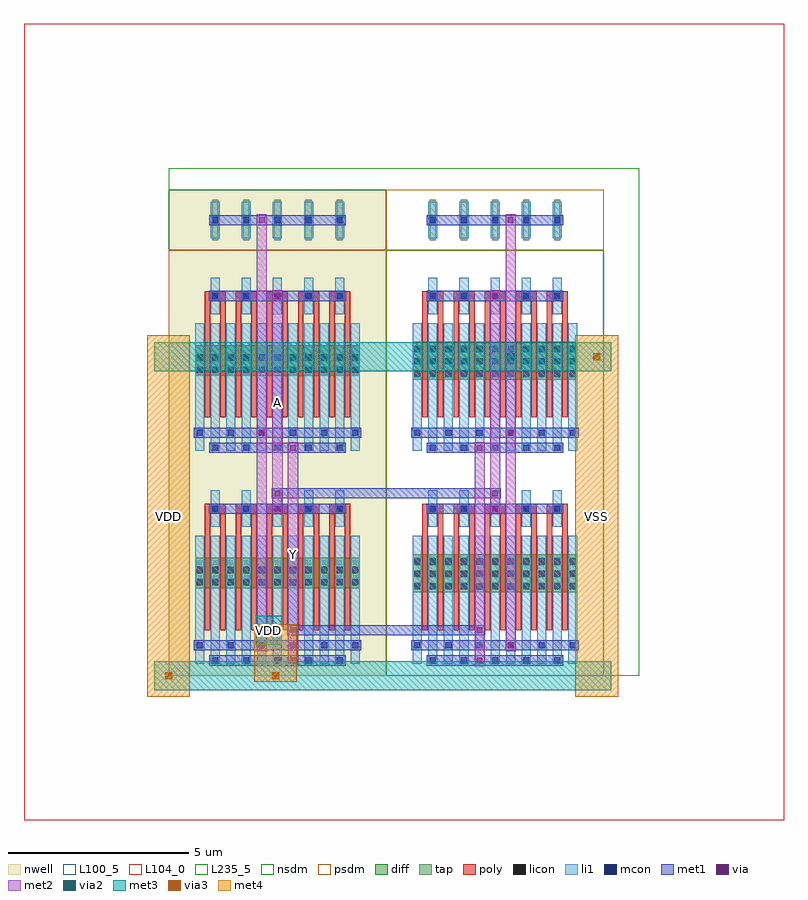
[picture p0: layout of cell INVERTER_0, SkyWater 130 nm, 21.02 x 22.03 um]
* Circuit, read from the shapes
.subckt INVERTER_0 A VDD VSS Y
XM1 Y A VSS VSS sky130_fd_pr__nfet_01v8 w=1.05 l=0.15 m=20
XM2 Y A VDD VDD sky130_fd_pr__pfet_01v8 w=0.84 l=0.15 m=20
.ends

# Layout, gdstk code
from math import pi, radians
import gdstk
lib = gdstk.Library(unit=1e-6, precision=1e-09)
def R(c, l, rs):  # rectangles x0, y0, x1, y1
    for r in rs: c.add(gdstk.rectangle(r[:2], r[2:], *l))
def A(c, l, x, y, w, h, nx, ny, dx, dy):  # array of equal rectangles
    R(c, l, [(x+i*dx, y+j*dy, x+i*dx+w, y+j*dy+h) for i in range(nx) for j in range(ny)])
def P(c, l, *ps):  # polygons
    for p in ps: c.add(gdstk.Polygon(p, *l))
nwell = (64, 20)
diff = (65, 20)
tap = (65, 44)
poly = (66, 20)
licon = (66, 44)
li1 = (67, 20)
mcon = (67, 44)
met1 = (68, 20)
via = (68, 44)
met2 = (69, 20)
via2 = (69, 44)
met3 = (70, 20)
via3 = (70, 44)
met4 = (71, 20)
nsdm = (93, 44)
psdm = (94, 20)
L100_5 = (100, 5)
L104_0 = (104, 0)
L235_5 = (235, 5)

nmos_s_6078655_x5_y2_167 = lib.new_cell('NMOS_S_6078655_X5_Y2_1678793193')
R(nmos_s_6078655_x5_y2_167, diff, [(0.735,2.31,5.285,3.36), (0.735,8.19,5.285,9.24)])
A(nmos_s_6078655_x5_y2_167, tap, 1.205, 12.04, 0.17, 1.12, 5, 1, 0.86, 0)
A(nmos_s_6078655_x5_y2_167, poly, 1, 1.26, 0.15, 3.36, 10, 2, 0.43, 5.88)
A(nmos_s_6078655_x5_y2_167, poly, 1, 4.485, 0.58, 0.27, 5, 2, 0.86, 5.88)
A(nmos_s_6078655_x5_y2_167, licon, 0.775, 2.39, 0.17, 0.17, 3, 3, 0.43, 0.34)
A(nmos_s_6078655_x5_y2_167, licon, 1.635, 2.39, 0.17, 0.17, 3, 3, 0.43, 0.34)
A(nmos_s_6078655_x5_y2_167, licon, 2.495, 2.39, 0.17, 0.17, 3, 3, 0.43, 0.34)
A(nmos_s_6078655_x5_y2_167, licon, 3.355, 2.39, 0.17, 0.17, 3, 3, 0.43, 0.34)
A(nmos_s_6078655_x5_y2_167, licon, 4.215, 2.39, 0.17, 0.17, 3, 3, 0.43, 0.34)
A(nmos_s_6078655_x5_y2_167, licon, 1.205, 4.535, 0.17, 0.17, 5, 2, 0.86, 5.88)
A(nmos_s_6078655_x5_y2_167, licon, 0.775, 8.27, 0.17, 0.17, 3, 3, 0.43, 0.34)
A(nmos_s_6078655_x5_y2_167, licon, 1.635, 8.27, 0.17, 0.17, 3, 3, 0.43, 0.34)
A(nmos_s_6078655_x5_y2_167, licon, 2.495, 8.27, 0.17, 0.17, 3, 3, 0.43, 0.34)
A(nmos_s_6078655_x5_y2_167, licon, 3.355, 8.27, 0.17, 0.17, 3, 3, 0.43, 0.34)
A(nmos_s_6078655_x5_y2_167, licon, 4.215, 8.27, 0.17, 0.17, 3, 3, 0.43, 0.34)
R(nmos_s_6078655_x5_y2_167, licon, [(1.205,12.515,1.375,12.685), (1.205,12.515,1.375,12.685), (2.065,12.515,2.235,12.685), (2.065,12.515,2.235,12.685), (2.925,12.515,3.095,12.685), (2.925,12.515,3.095,12.685), (3.785,12.515,3.955,12.685), (3.785,12.515,3.955,12.685), (4.645,12.515,4.815,12.685), (4.645,12.515,4.815,12.685)])
A(nmos_s_6078655_x5_y2_167, li1, 0.735, 0.335, 0.25, 3.53, 11, 2, 0.43, 5.88)
A(nmos_s_6078655_x5_y2_167, li1, 1.165, 4.115, 0.25, 1.01, 5, 2, 0.86, 5.88)
A(nmos_s_6078655_x5_y2_167, li1, 1.165, 12.095, 0.25, 1.01, 5, 1, 0.86, 0)
A(nmos_s_6078655_x5_y2_167, mcon, 1.205, 0.335, 0.17, 0.17, 5, 2, 0.86, 4.2)
A(nmos_s_6078655_x5_y2_167, mcon, 0.775, 0.755, 0.17, 0.17, 6, 2, 0.86, 5.88)
A(nmos_s_6078655_x5_y2_167, mcon, 1.205, 6.215, 0.17, 0.17, 5, 2, 0.86, 4.2)
A(nmos_s_6078655_x5_y2_167, mcon, 1.205, 12.515, 0.17, 0.17, 5, 1, 0.86, 0)
R(nmos_s_6078655_x5_y2_167, met1, [(1.12,0.28,4.9,0.56), (0.69,0.7,5.33,0.98), (1.12,4.48,4.9,4.76), (1.12,6.16,4.9,6.44), (0.69,6.58,5.33,6.86), (1.12,10.36,4.9,10.64), (1.12,12.46,4.9,12.74)])
A(nmos_s_6078655_x5_y2_167, via, 3.365, 0.765, 0.15, 0.15, 1, 3, 0, 5.88)
R(nmos_s_6078655_x5_y2_167, via, [(2.505,0.345,2.655,0.495), (2.935,4.545,3.085,4.695), (2.505,6.225,2.655,6.375), (2.935,10.425,3.085,10.575)])
R(nmos_s_6078655_x5_y2_167, met2, [(2.44,0.26,2.72,6.46), (3.3,0.68,3.58,12.76), (2.87,4.46,3.15,10.66)])
R(nmos_s_6078655_x5_y2_167, nsdm, [(0,0,6.02,11.76)])
R(nmos_s_6078655_x5_y2_167, psdm, [(0,11.76,6.02,13.44)])
R(nmos_s_6078655_x5_y2_167, L100_5, [(0,0,6.02,13.44)])

pmos_s_79543009_x5_y2_16 = lib.new_cell('PMOS_S_79543009_X5_Y2_1678793194')
R(pmos_s_79543009_x5_y2_16, nwell, [(0,0,6.02,13.44)])
R(pmos_s_79543009_x5_y2_16, diff, [(0.735,2.415,5.285,3.255), (0.735,8.295,5.285,9.135)])
A(pmos_s_79543009_x5_y2_16, tap, 1.205, 12.04, 0.17, 1.12, 5, 1, 0.86, 0)
A(pmos_s_79543009_x5_y2_16, poly, 1, 1.26, 0.15, 3.36, 10, 2, 0.43, 5.88)
A(pmos_s_79543009_x5_y2_16, poly, 1, 4.485, 0.58, 0.27, 5, 2, 0.86, 5.88)
A(pmos_s_79543009_x5_y2_16, licon, 0.775, 2.495, 0.17, 0.17, 3, 2, 0.43, 0.34)
A(pmos_s_79543009_x5_y2_16, licon, 1.635, 2.495, 0.17, 0.17, 3, 2, 0.43, 0.34)
A(pmos_s_79543009_x5_y2_16, licon, 2.495, 2.495, 0.17, 0.17, 3, 2, 0.43, 0.34)
A(pmos_s_79543009_x5_y2_16, licon, 3.355, 2.495, 0.17, 0.17, 3, 2, 0.43, 0.34)
A(pmos_s_79543009_x5_y2_16, licon, 4.215, 2.495, 0.17, 0.17, 3, 2, 0.43, 0.34)
A(pmos_s_79543009_x5_y2_16, licon, 1.205, 4.535, 0.17, 0.17, 5, 2, 0.86, 5.88)
A(pmos_s_79543009_x5_y2_16, licon, 0.775, 8.375, 0.17, 0.17, 3, 2, 0.43, 0.34)
A(pmos_s_79543009_x5_y2_16, licon, 1.635, 8.375, 0.17, 0.17, 3, 2, 0.43, 0.34)
A(pmos_s_79543009_x5_y2_16, licon, 2.495, 8.375, 0.17, 0.17, 3, 2, 0.43, 0.34)
A(pmos_s_79543009_x5_y2_16, licon, 3.355, 8.375, 0.17, 0.17, 3, 2, 0.43, 0.34)
A(pmos_s_79543009_x5_y2_16, licon, 4.215, 8.375, 0.17, 0.17, 3, 2, 0.43, 0.34)
R(pmos_s_79543009_x5_y2_16, licon, [(1.205,12.515,1.375,12.685), (1.205,12.515,1.375,12.685), (2.065,12.515,2.235,12.685), (2.065,12.515,2.235,12.685), (2.925,12.515,3.095,12.685), (2.925,12.515,3.095,12.685), (3.785,12.515,3.955,12.685), (3.785,12.515,3.955,12.685), (4.645,12.515,4.815,12.685), (4.645,12.515,4.815,12.685)])
A(pmos_s_79543009_x5_y2_16, li1, 0.735, 0.335, 0.25, 3.53, 11, 2, 0.43, 5.88)
A(pmos_s_79543009_x5_y2_16, li1, 1.165, 4.115, 0.25, 1.01, 5, 2, 0.86, 5.88)
A(pmos_s_79543009_x5_y2_16, li1, 1.165, 12.095, 0.25, 1.01, 5, 1, 0.86, 0)
A(pmos_s_79543009_x5_y2_16, mcon, 1.205, 0.335, 0.17, 0.17, 5, 2, 0.86, 4.2)
A(pmos_s_79543009_x5_y2_16, mcon, 0.775, 0.755, 0.17, 0.17, 6, 2, 0.86, 5.88)
A(pmos_s_79543009_x5_y2_16, mcon, 1.205, 6.215, 0.17, 0.17, 5, 2, 0.86, 4.2)
A(pmos_s_79543009_x5_y2_16, mcon, 1.205, 12.515, 0.17, 0.17, 5, 1, 0.86, 0)
R(pmos_s_79543009_x5_y2_16, met1, [(1.12,0.28,4.9,0.56), (0.69,0.7,5.33,0.98), (1.12,4.48,4.9,4.76), (1.12,6.16,4.9,6.44), (0.69,6.58,5.33,6.86), (1.12,10.36,4.9,10.64), (1.12,12.46,4.9,12.74)])
A(pmos_s_79543009_x5_y2_16, via, 3.365, 0.765, 0.15, 0.15, 1, 3, 0, 5.88)
R(pmos_s_79543009_x5_y2_16, via, [(2.505,0.345,2.655,0.495), (2.935,4.545,3.085,4.695), (2.505,6.225,2.655,6.375), (2.935,10.425,3.085,10.575)])
R(pmos_s_79543009_x5_y2_16, met2, [(2.44,0.26,2.72,6.46), (3.3,0.68,3.58,12.76), (2.87,4.46,3.15,10.66)])
R(pmos_s_79543009_x5_y2_16, nsdm, [(0,11.76,6.02,13.44)])
R(pmos_s_79543009_x5_y2_16, psdm, [(0,0,6.02,11.76)])
R(pmos_s_79543009_x5_y2_16, L100_5, [(0,0,6.02,13.44)])

inverter_0 = lib.new_cell('INVERTER_0')
R(inverter_0, met1, [(3.28,1.12,3.6,1.4), (3.28,1.12,3.6,1.4), (3.44,1.12,8.6,1.4), (8.44,1.12,8.76,1.4), (8.44,1.12,8.76,1.4), (2.85,4.9,3.17,5.18), (2.85,4.9,3.17,5.18), (3.01,4.9,9.03,5.18), (8.87,4.9,9.19,5.18), (8.87,4.9,9.19,5.18)])
R(inverter_0, via, [(3.365,1.185,3.515,1.335), (3.365,1.185,3.515,1.335), (8.525,1.185,8.675,1.335), (8.525,1.185,8.675,1.335), (2.935,4.965,3.085,5.115), (2.935,4.965,3.085,5.115), (8.955,4.965,9.105,5.115), (8.955,4.965,9.105,5.115)])
R(inverter_0, met2, [(2.44,1.075,2.72,1.445), (2.44,1.075,2.72,1.445), (3.3,1.1,3.58,1.42), (3.3,1.1,3.58,1.42), (8.46,1.1,8.74,1.42), (8.46,1.1,8.74,1.42), (2.87,4.88,3.15,5.2), (2.87,4.88,3.15,5.2), (8.89,4.88,9.17,5.2), (8.89,4.88,9.17,5.2), (9.32,8.635,9.6,9.005), (9.32,8.635,9.6,9.005)])
P(inverter_0, met2, [(0,0),(0,0),(0,0),(0,0)],
  [(0,0),(0,0),(0,0),(0,0)],
  [(0,0),(0,0),(0,0),(0,0)],
  [(0,0),(0,0),(0,0),(0,0)],
  [(0,0),(0,0),(0,0),(0,0)],
  [(0,0),(0,0),(0,0),(0,0)],
  [(0,0),(0,0),(0,0),(0,0)],
  [(0,0),(0,0),(0,0),(0,0)])
R(inverter_0, via2, [(2.48,1.16,2.68,1.36), (2.48,1.16,2.68,1.36), (9.36,8.72,9.56,8.92), (9.36,8.72,9.56,8.92)])
A(inverter_0, met3, -0.4, -0.4, 4.24, 0.8, 3, 2, 3.44, 8.82)
R(inverter_0, met3, [(-0.165,-0.4,0.165,0.4), (2.795,-0.4,3.125,0.4), (2.795,-0.4,3.125,0.4), (9.92,-0.4,12.24,0.4), (2.415,0.86,2.745,1.66), (2.415,0.86,2.745,1.66), (2.58,0.86,2.96,1.66), (2.795,0.86,3.125,1.66), (2.795,0.86,3.125,1.66), (9.295,8.42,9.625,9.22), (9.295,8.42,9.625,9.22), (9.92,8.42,12.24,9.22), (11.675,8.42,12.005,9.22)])
R(inverter_0, via3, [(-0.1,-0.1,0.1,0.1), (2.86,-0.1,3.06,0.1), (2.86,-0.1,3.06,0.1), (2.86,1.16,3.06,1.36), (2.86,1.16,3.06,1.36), (11.74,8.72,11.94,8.92)])
R(inverter_0, met4, [(-0.59,-0.59,0.59,9.41), (11.25,-0.59,12.43,9.41), (-0.59,-0.165,0.59,0.165), (2.37,-0.165,3.55,0.165), (2.37,-0.165,3.55,0.165), (2.37,0,3.55,1.26), (2.37,1.095,3.55,1.425), (2.37,1.095,3.55,1.425), (11.25,8.655,12.43,8.985)])
R(inverter_0, L104_0, [(-4,-4,17.02,18.03)])
R(inverter_0, L235_5, [(0,0,13.02,14.03)])
inverter_0.add(gdstk.Reference(nmos_s_6078655_x5_y2_167, (6.02,0)))
inverter_0.add(gdstk.Reference(pmos_s_79543009_x5_y2_16, (6.02,0), rotation=pi, x_reflection=True))
inverter_0.add(gdstk.Label('Y', (3.44,3.36), layer=69, texttype=5))
inverter_0.add(gdstk.Label('A', (3.01,7.56), layer=69, texttype=5))
inverter_0.add(gdstk.Label('VSS', (11.84,4.41), layer=71, texttype=5))
inverter_0.add(gdstk.Label('VSS', (11.84,4.41), layer=71, texttype=5))
inverter_0.add(gdstk.Label('VDD', (0,4.41), layer=71, texttype=5))
inverter_0.add(gdstk.Label('VDD', (2.77,1.26), layer=70, texttype=5))
inverter_0.add(gdstk.Label('VDD', (0,4.41), layer=71, texttype=5))
inverter_0.add(gdstk.Label('VDD', (0,4.41), layer=71, texttype=5))
inverter_0.add(gdstk.Label('VDD', (0,4.41), layer=71, texttype=5))

lib.write_gds('INVERTER_0.gds')
